VERSION 5.7 ;
  NOWIREEXTENSIONATPIN ON ;
  DIVIDERCHAR "/" ;
  BUSBITCHARS "[]" ;
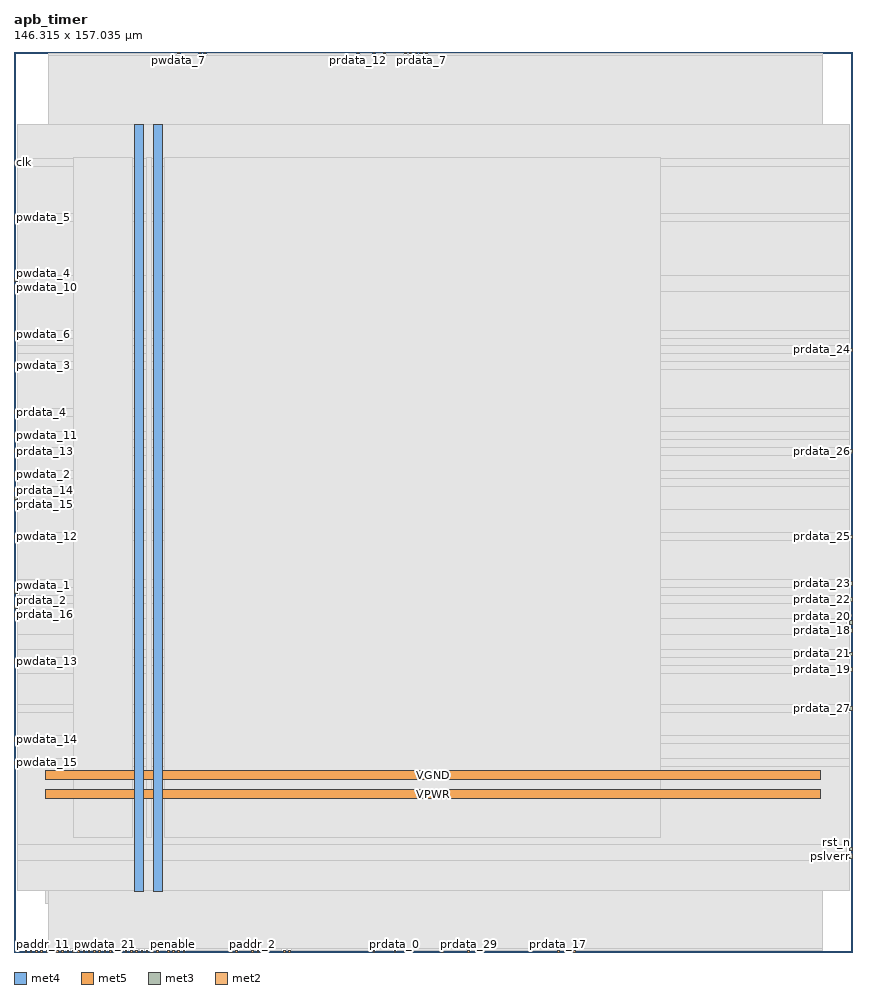
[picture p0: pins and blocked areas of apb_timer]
MACRO apb_timer
  CLASS BLOCK ;
  FOREIGN apb_timer ;
  ORIGIN 0.000 0.000 ;
  SIZE 146.315 BY 157.035 ;
  PIN VGND
    DIRECTION INOUT ;
    USE GROUND ;
    PORT
      LAYER met4 ;
        RECT 24.340 10.640 25.940 144.400 ;
    END
    PORT
      LAYER met5 ;
        RECT 5.520 30.030 140.760 31.630 ;
    END
  END VGND
  PIN VPWR
    DIRECTION INOUT ;
    USE POWER ;
    PORT
      LAYER met4 ;
        RECT 21.040 10.640 22.640 144.400 ;
    END
    PORT
      LAYER met5 ;
        RECT 5.520 26.730 140.760 28.330 ;
    END
  END VPWR
  PIN clk
    DIRECTION INPUT ;
    USE SIGNAL ;
    ANTENNAGATEAREA 1.286700 ;
    ANTENNADIFFAREA 0.434700 ;
    PORT
      LAYER met3 ;
        RECT 0.000 137.400 0.600 138.000 ;
    END
  END clk
  PIN paddr_0
    DIRECTION INPUT ;
    USE SIGNAL ;
    PORT
      LAYER met2 ;
        RECT 1.930 0.000 2.210 0.280 ;
    END
  END paddr_0
  PIN paddr_1
    DIRECTION INPUT ;
    USE SIGNAL ;
    PORT
      LAYER met2 ;
        RECT 2.850 0.000 3.130 0.280 ;
    END
  END paddr_1
  PIN paddr_10
    DIRECTION INPUT ;
    USE SIGNAL ;
    PORT
      LAYER met2 ;
        RECT 3.770 0.000 4.050 0.280 ;
    END
  END paddr_10
  PIN paddr_11
    DIRECTION INPUT ;
    USE SIGNAL ;
    PORT
      LAYER met2 ;
        RECT 4.690 0.000 4.970 0.280 ;
    END
  END paddr_11
  PIN paddr_2
    DIRECTION INPUT ;
    USE SIGNAL ;
    ANTENNAGATEAREA 0.647700 ;
    ANTENNADIFFAREA 0.434700 ;
    PORT
      LAYER met2 ;
        RECT 41.490 0.000 41.770 0.280 ;
    END
  END paddr_2
  PIN paddr_3
    DIRECTION INPUT ;
    USE SIGNAL ;
    ANTENNAGATEAREA 0.647700 ;
    ANTENNADIFFAREA 0.434700 ;
    PORT
      LAYER met2 ;
        RECT 38.730 0.000 39.010 0.280 ;
    END
  END paddr_3
  PIN paddr_4
    DIRECTION INPUT ;
    USE SIGNAL ;
    ANTENNAGATEAREA 0.647700 ;
    ANTENNADIFFAREA 0.434700 ;
    PORT
      LAYER met2 ;
        RECT 37.810 0.000 38.090 0.280 ;
    END
  END paddr_4
  PIN paddr_5
    DIRECTION INPUT ;
    USE SIGNAL ;
    PORT
      LAYER met2 ;
        RECT 5.610 0.000 5.890 0.280 ;
    END
  END paddr_5
  PIN paddr_6
    DIRECTION INPUT ;
    USE SIGNAL ;
    PORT
      LAYER met2 ;
        RECT 6.530 0.000 6.810 0.280 ;
    END
  END paddr_6
  PIN paddr_7
    DIRECTION INPUT ;
    USE SIGNAL ;
    PORT
      LAYER met2 ;
        RECT 7.450 0.000 7.730 0.280 ;
    END
  END paddr_7
  PIN paddr_8
    DIRECTION INPUT ;
    USE SIGNAL ;
    PORT
      LAYER met2 ;
        RECT 8.370 0.000 8.650 0.280 ;
    END
  END paddr_8
  PIN paddr_9
    DIRECTION INPUT ;
    USE SIGNAL ;
    PORT
      LAYER met2 ;
        RECT 9.290 0.000 9.570 0.280 ;
    END
  END paddr_9
  PIN penable
    DIRECTION INPUT ;
    USE SIGNAL ;
    ANTENNAGATEAREA 0.647700 ;
    ANTENNADIFFAREA 0.434700 ;
    PORT
      LAYER met2 ;
        RECT 27.690 0.000 27.970 0.280 ;
    END
  END penable
  PIN prdata_0
    DIRECTION OUTPUT ;
    USE SIGNAL ;
    ANTENNAGATEAREA 0.560700 ;
    ANTENNADIFFAREA 0.863700 ;
    PORT
      LAYER met2 ;
        RECT 66.330 0.000 66.610 0.280 ;
    END
  END prdata_0
  PIN prdata_1
    DIRECTION OUTPUT ;
    USE SIGNAL ;
    ANTENNAGATEAREA 0.560700 ;
    ANTENNADIFFAREA 0.863700 ;
    PORT
      LAYER met2 ;
        RECT 47.010 0.000 47.290 0.280 ;
    END
  END prdata_1
  PIN prdata_10
    DIRECTION OUTPUT ;
    USE SIGNAL ;
    ANTENNAGATEAREA 0.434700 ;
    ANTENNADIFFAREA 1.137600 ;
    PORT
      LAYER met2 ;
        RECT 68.170 156.755 68.450 157.035 ;
    END
  END prdata_10
  PIN prdata_11
    DIRECTION OUTPUT ;
    USE SIGNAL ;
    ANTENNAGATEAREA 0.434700 ;
    ANTENNADIFFAREA 1.137600 ;
    PORT
      LAYER met2 ;
        RECT 69.090 156.755 69.370 157.035 ;
    END
  END prdata_11
  PIN prdata_12
    DIRECTION OUTPUT ;
    USE SIGNAL ;
    ANTENNAGATEAREA 0.434700 ;
    ANTENNADIFFAREA 1.137600 ;
    PORT
      LAYER met2 ;
        RECT 59.890 156.755 60.170 157.035 ;
    END
  END prdata_12
  PIN prdata_13
    DIRECTION OUTPUT ;
    USE SIGNAL ;
    ANTENNAGATEAREA 0.434700 ;
    ANTENNADIFFAREA 1.137600 ;
    PORT
      LAYER met3 ;
        RECT 0.000 87.080 0.600 87.680 ;
    END
  END prdata_13
  PIN prdata_14
    DIRECTION OUTPUT ;
    USE SIGNAL ;
    ANTENNAGATEAREA 0.560700 ;
    ANTENNADIFFAREA 0.863700 ;
    PORT
      LAYER met3 ;
        RECT 0.000 80.280 0.600 80.880 ;
    END
  END prdata_14
  PIN prdata_15
    DIRECTION OUTPUT ;
    USE SIGNAL ;
    ANTENNAGATEAREA 0.434700 ;
    ANTENNADIFFAREA 1.137600 ;
    PORT
      LAYER met3 ;
        RECT 0.000 78.920 0.600 79.520 ;
    END
  END prdata_15
  PIN prdata_16
    DIRECTION OUTPUT ;
    USE SIGNAL ;
    ANTENNAGATEAREA 0.434700 ;
    ANTENNADIFFAREA 1.137600 ;
    PORT
      LAYER met3 ;
        RECT 0.000 58.520 0.600 59.120 ;
    END
  END prdata_16
  PIN prdata_17
    DIRECTION OUTPUT ;
    USE SIGNAL ;
    ANTENNAGATEAREA 0.434700 ;
    ANTENNADIFFAREA 1.137600 ;
    PORT
      LAYER met2 ;
        RECT 94.850 0.000 95.130 0.280 ;
    END
  END prdata_17
  PIN prdata_18
    DIRECTION OUTPUT ;
    USE SIGNAL ;
    ANTENNAGATEAREA 0.434700 ;
    ANTENNADIFFAREA 1.137600 ;
    PORT
      LAYER met3 ;
        RECT 145.715 55.800 146.315 56.400 ;
    END
  END prdata_18
  PIN prdata_19
    DIRECTION OUTPUT ;
    USE SIGNAL ;
    ANTENNAGATEAREA 0.434700 ;
    ANTENNADIFFAREA 1.137600 ;
    PORT
      LAYER met3 ;
        RECT 145.715 49.000 146.315 49.600 ;
    END
  END prdata_19
  PIN prdata_2
    DIRECTION OUTPUT ;
    USE SIGNAL ;
    ANTENNAGATEAREA 0.560700 ;
    ANTENNADIFFAREA 0.863700 ;
    PORT
      LAYER met3 ;
        RECT 0.000 59.880 0.600 60.480 ;
    END
  END prdata_2
  PIN prdata_20
    DIRECTION OUTPUT ;
    USE SIGNAL ;
    ANTENNAGATEAREA 0.434700 ;
    ANTENNADIFFAREA 1.137600 ;
    PORT
      LAYER met3 ;
        RECT 145.715 57.160 146.315 57.760 ;
    END
  END prdata_20
  PIN prdata_21
    DIRECTION OUTPUT ;
    USE SIGNAL ;
    ANTENNAGATEAREA 0.434700 ;
    ANTENNADIFFAREA 1.137600 ;
    PORT
      LAYER met3 ;
        RECT 145.715 51.720 146.315 52.320 ;
    END
  END prdata_21
  PIN prdata_22
    DIRECTION OUTPUT ;
    USE SIGNAL ;
    ANTENNAGATEAREA 0.434700 ;
    ANTENNADIFFAREA 1.137600 ;
    PORT
      LAYER met3 ;
        RECT 145.715 61.240 146.315 61.840 ;
    END
  END prdata_22
  PIN prdata_23
    DIRECTION OUTPUT ;
    USE SIGNAL ;
    ANTENNAGATEAREA 0.434700 ;
    ANTENNADIFFAREA 1.137600 ;
    PORT
      LAYER met3 ;
        RECT 145.715 63.960 146.315 64.560 ;
    END
  END prdata_23
  PIN prdata_24
    DIRECTION OUTPUT ;
    USE SIGNAL ;
    ANTENNAGATEAREA 0.434700 ;
    ANTENNADIFFAREA 1.137600 ;
    PORT
      LAYER met3 ;
        RECT 145.715 104.760 146.315 105.360 ;
    END
  END prdata_24
  PIN prdata_25
    DIRECTION OUTPUT ;
    USE SIGNAL ;
    ANTENNAGATEAREA 0.434700 ;
    ANTENNADIFFAREA 1.137600 ;
    PORT
      LAYER met3 ;
        RECT 145.715 72.120 146.315 72.720 ;
    END
  END prdata_25
  PIN prdata_26
    DIRECTION OUTPUT ;
    USE SIGNAL ;
    ANTENNAGATEAREA 0.434700 ;
    ANTENNADIFFAREA 1.137600 ;
    PORT
      LAYER met3 ;
        RECT 145.715 87.080 146.315 87.680 ;
    END
  END prdata_26
  PIN prdata_27
    DIRECTION OUTPUT ;
    USE SIGNAL ;
    ANTENNAGATEAREA 0.434700 ;
    ANTENNADIFFAREA 1.137600 ;
    PORT
      LAYER met3 ;
        RECT 145.715 42.200 146.315 42.800 ;
    END
  END prdata_27
  PIN prdata_28
    DIRECTION OUTPUT ;
    USE SIGNAL ;
    ANTENNAGATEAREA 0.434700 ;
    ANTENNADIFFAREA 1.137600 ;
    PORT
      LAYER met2 ;
        RECT 97.610 0.000 97.890 0.280 ;
    END
  END prdata_28
  PIN prdata_29
    DIRECTION OUTPUT ;
    USE SIGNAL ;
    ANTENNAGATEAREA 0.434700 ;
    ANTENNADIFFAREA 1.137600 ;
    PORT
      LAYER met2 ;
        RECT 79.210 0.000 79.490 0.280 ;
    END
  END prdata_29
  PIN prdata_3
    DIRECTION OUTPUT ;
    USE SIGNAL ;
    ANTENNAGATEAREA 0.560700 ;
    ANTENNADIFFAREA 0.863700 ;
    PORT
      LAYER met3 ;
        RECT 0.000 77.560 0.600 78.160 ;
    END
  END prdata_3
  PIN prdata_30
    DIRECTION OUTPUT ;
    USE SIGNAL ;
    ANTENNAGATEAREA 0.434700 ;
    ANTENNADIFFAREA 1.137600 ;
    PORT
      LAYER met2 ;
        RECT 74.610 0.000 74.890 0.280 ;
    END
  END prdata_30
  PIN prdata_31
    DIRECTION OUTPUT ;
    USE SIGNAL ;
    ANTENNAGATEAREA 0.560700 ;
    ANTENNADIFFAREA 0.863700 ;
    PORT
      LAYER met2 ;
        RECT 47.930 0.000 48.210 0.280 ;
    END
  END prdata_31
  PIN prdata_4
    DIRECTION OUTPUT ;
    USE SIGNAL ;
    ANTENNAGATEAREA 0.434700 ;
    ANTENNADIFFAREA 1.137600 ;
    PORT
      LAYER met3 ;
        RECT 0.000 93.880 0.600 94.480 ;
    END
  END prdata_4
  PIN prdata_5
    DIRECTION OUTPUT ;
    USE SIGNAL ;
    ANTENNAGATEAREA 0.434700 ;
    ANTENNADIFFAREA 1.137600 ;
    PORT
      LAYER met2 ;
        RECT 64.490 156.755 64.770 157.035 ;
    END
  END prdata_5
  PIN prdata_6
    DIRECTION OUTPUT ;
    USE SIGNAL ;
    ANTENNAGATEAREA 0.434700 ;
    ANTENNADIFFAREA 1.137600 ;
    PORT
      LAYER met2 ;
        RECT 71.850 156.755 72.130 157.035 ;
    END
  END prdata_6
  PIN prdata_7
    DIRECTION OUTPUT ;
    USE SIGNAL ;
    ANTENNAGATEAREA 0.434700 ;
    ANTENNADIFFAREA 1.137600 ;
    PORT
      LAYER met2 ;
        RECT 70.930 156.755 71.210 157.035 ;
    END
  END prdata_7
  PIN prdata_8
    DIRECTION OUTPUT ;
    USE SIGNAL ;
    ANTENNAGATEAREA 0.434700 ;
    ANTENNADIFFAREA 1.137600 ;
    PORT
      LAYER met2 ;
        RECT 70.010 156.755 70.290 157.035 ;
    END
  END prdata_8
  PIN prdata_9
    DIRECTION OUTPUT ;
    USE SIGNAL ;
    ANTENNAGATEAREA 0.434700 ;
    ANTENNADIFFAREA 1.137600 ;
    PORT
      LAYER met2 ;
        RECT 62.650 156.755 62.930 157.035 ;
    END
  END prdata_9
  PIN pready
    DIRECTION OUTPUT ;
    USE SIGNAL ;
    PORT
      LAYER met2 ;
        RECT 10.210 0.000 10.490 0.280 ;
    END
  END pready
  PIN psel
    DIRECTION INPUT ;
    USE SIGNAL ;
    ANTENNAGATEAREA 0.647700 ;
    ANTENNADIFFAREA 0.434700 ;
    PORT
      LAYER met2 ;
        RECT 28.610 0.000 28.890 0.280 ;
    END
  END psel
  PIN pslverr
    DIRECTION OUTPUT ;
    USE SIGNAL ;
    ANTENNAGATEAREA 0.434700 ;
    ANTENNADIFFAREA 0.775300 ;
    PORT
      LAYER met3 ;
        RECT 145.715 16.360 146.315 16.960 ;
    END
  END pslverr
  PIN pwdata_0
    DIRECTION INPUT ;
    USE SIGNAL ;
    ANTENNAGATEAREA 0.647700 ;
    ANTENNADIFFAREA 0.434700 ;
    PORT
      LAYER met2 ;
        RECT 29.530 0.000 29.810 0.280 ;
    END
  END pwdata_0
  PIN pwdata_1
    DIRECTION INPUT ;
    USE SIGNAL ;
    ANTENNAGATEAREA 0.647700 ;
    ANTENNADIFFAREA 0.434700 ;
    PORT
      LAYER met3 ;
        RECT 0.000 62.600 0.600 63.200 ;
    END
  END pwdata_1
  PIN pwdata_10
    DIRECTION INPUT ;
    USE SIGNAL ;
    ANTENNAGATEAREA 0.647700 ;
    ANTENNADIFFAREA 0.434700 ;
    PORT
      LAYER met3 ;
        RECT 0.000 115.640 0.600 116.240 ;
    END
  END pwdata_10
  PIN pwdata_11
    DIRECTION INPUT ;
    USE SIGNAL ;
    ANTENNAGATEAREA 0.647700 ;
    ANTENNADIFFAREA 0.434700 ;
    PORT
      LAYER met3 ;
        RECT 0.000 89.800 0.600 90.400 ;
    END
  END pwdata_11
  PIN pwdata_12
    DIRECTION INPUT ;
    USE SIGNAL ;
    ANTENNAGATEAREA 0.647700 ;
    ANTENNADIFFAREA 0.434700 ;
    PORT
      LAYER met3 ;
        RECT 0.000 72.120 0.600 72.720 ;
    END
  END pwdata_12
  PIN pwdata_13
    DIRECTION INPUT ;
    USE SIGNAL ;
    ANTENNAGATEAREA 0.647700 ;
    ANTENNADIFFAREA 0.434700 ;
    PORT
      LAYER met3 ;
        RECT 0.000 50.360 0.600 50.960 ;
    END
  END pwdata_13
  PIN pwdata_14
    DIRECTION INPUT ;
    USE SIGNAL ;
    ANTENNAGATEAREA 0.647700 ;
    ANTENNADIFFAREA 0.434700 ;
    PORT
      LAYER met3 ;
        RECT 0.000 36.760 0.600 37.360 ;
    END
  END pwdata_14
  PIN pwdata_15
    DIRECTION INPUT ;
    USE SIGNAL ;
    ANTENNAGATEAREA 0.647700 ;
    ANTENNADIFFAREA 0.434700 ;
    PORT
      LAYER met3 ;
        RECT 0.000 32.680 0.600 33.280 ;
    END
  END pwdata_15
  PIN pwdata_16
    DIRECTION INPUT ;
    USE SIGNAL ;
    PORT
      LAYER met2 ;
        RECT 11.130 0.000 11.410 0.280 ;
    END
  END pwdata_16
  PIN pwdata_17
    DIRECTION INPUT ;
    USE SIGNAL ;
    PORT
      LAYER met2 ;
        RECT 12.050 0.000 12.330 0.280 ;
    END
  END pwdata_17
  PIN pwdata_18
    DIRECTION INPUT ;
    USE SIGNAL ;
    PORT
      LAYER met2 ;
        RECT 12.970 0.000 13.250 0.280 ;
    END
  END pwdata_18
  PIN pwdata_19
    DIRECTION INPUT ;
    USE SIGNAL ;
    PORT
      LAYER met2 ;
        RECT 13.890 0.000 14.170 0.280 ;
    END
  END pwdata_19
  PIN pwdata_2
    DIRECTION INPUT ;
    USE SIGNAL ;
    ANTENNAGATEAREA 0.647700 ;
    ANTENNADIFFAREA 0.434700 ;
    PORT
      LAYER met3 ;
        RECT 0.000 83.000 0.600 83.600 ;
    END
  END pwdata_2
  PIN pwdata_20
    DIRECTION INPUT ;
    USE SIGNAL ;
    PORT
      LAYER met2 ;
        RECT 14.810 0.000 15.090 0.280 ;
    END
  END pwdata_20
  PIN pwdata_21
    DIRECTION INPUT ;
    USE SIGNAL ;
    PORT
      LAYER met2 ;
        RECT 15.730 0.000 16.010 0.280 ;
    END
  END pwdata_21
  PIN pwdata_22
    DIRECTION INPUT ;
    USE SIGNAL ;
    PORT
      LAYER met2 ;
        RECT 16.650 0.000 16.930 0.280 ;
    END
  END pwdata_22
  PIN pwdata_23
    DIRECTION INPUT ;
    USE SIGNAL ;
    PORT
      LAYER met2 ;
        RECT 17.570 0.000 17.850 0.280 ;
    END
  END pwdata_23
  PIN pwdata_24
    DIRECTION INPUT ;
    USE SIGNAL ;
    PORT
      LAYER met2 ;
        RECT 18.490 0.000 18.770 0.280 ;
    END
  END pwdata_24
  PIN pwdata_25
    DIRECTION INPUT ;
    USE SIGNAL ;
    PORT
      LAYER met2 ;
        RECT 19.410 0.000 19.690 0.280 ;
    END
  END pwdata_25
  PIN pwdata_26
    DIRECTION INPUT ;
    USE SIGNAL ;
    PORT
      LAYER met2 ;
        RECT 20.330 0.000 20.610 0.280 ;
    END
  END pwdata_26
  PIN pwdata_27
    DIRECTION INPUT ;
    USE SIGNAL ;
    PORT
      LAYER met2 ;
        RECT 21.250 0.000 21.530 0.280 ;
    END
  END pwdata_27
  PIN pwdata_28
    DIRECTION INPUT ;
    USE SIGNAL ;
    PORT
      LAYER met2 ;
        RECT 22.170 0.000 22.450 0.280 ;
    END
  END pwdata_28
  PIN pwdata_29
    DIRECTION INPUT ;
    USE SIGNAL ;
    PORT
      LAYER met2 ;
        RECT 23.090 0.000 23.370 0.280 ;
    END
  END pwdata_29
  PIN pwdata_3
    DIRECTION INPUT ;
    USE SIGNAL ;
    ANTENNAGATEAREA 0.647700 ;
    ANTENNADIFFAREA 0.434700 ;
    PORT
      LAYER met3 ;
        RECT 0.000 102.040 0.600 102.640 ;
    END
  END pwdata_3
  PIN pwdata_30
    DIRECTION INPUT ;
    USE SIGNAL ;
    PORT
      LAYER met2 ;
        RECT 24.010 0.000 24.290 0.280 ;
    END
  END pwdata_30
  PIN pwdata_31
    DIRECTION INPUT ;
    USE SIGNAL ;
    PORT
      LAYER met2 ;
        RECT 24.930 0.000 25.210 0.280 ;
    END
  END pwdata_31
  PIN pwdata_4
    DIRECTION INPUT ;
    USE SIGNAL ;
    ANTENNAGATEAREA 0.647700 ;
    ANTENNADIFFAREA 0.434700 ;
    PORT
      LAYER met3 ;
        RECT 0.000 117.000 0.600 117.600 ;
    END
  END pwdata_4
  PIN pwdata_5
    DIRECTION INPUT ;
    USE SIGNAL ;
    ANTENNAGATEAREA 0.647700 ;
    ANTENNADIFFAREA 0.434700 ;
    PORT
      LAYER met3 ;
        RECT 0.000 127.880 0.600 128.480 ;
    END
  END pwdata_5
  PIN pwdata_6
    DIRECTION INPUT ;
    USE SIGNAL ;
    ANTENNAGATEAREA 0.647700 ;
    ANTENNADIFFAREA 0.434700 ;
    PORT
      LAYER met3 ;
        RECT 0.000 107.480 0.600 108.080 ;
    END
  END pwdata_6
  PIN pwdata_7
    DIRECTION INPUT ;
    USE SIGNAL ;
    ANTENNAGATEAREA 0.647700 ;
    ANTENNADIFFAREA 0.434700 ;
    PORT
      LAYER met2 ;
        RECT 28.610 156.755 28.890 157.035 ;
    END
  END pwdata_7
  PIN pwdata_8
    DIRECTION INPUT ;
    USE SIGNAL ;
    ANTENNAGATEAREA 0.647700 ;
    ANTENNADIFFAREA 0.434700 ;
    PORT
      LAYER met2 ;
        RECT 33.210 156.755 33.490 157.035 ;
    END
  END pwdata_8
  PIN pwdata_9
    DIRECTION INPUT ;
    USE SIGNAL ;
    ANTENNAGATEAREA 0.647700 ;
    ANTENNADIFFAREA 0.434700 ;
    PORT
      LAYER met2 ;
        RECT 32.290 156.755 32.570 157.035 ;
    END
  END pwdata_9
  PIN pwrite
    DIRECTION INPUT ;
    USE SIGNAL ;
    ANTENNAGATEAREA 0.647700 ;
    ANTENNADIFFAREA 0.434700 ;
    PORT
      LAYER met2 ;
        RECT 26.770 0.000 27.050 0.280 ;
    END
  END pwrite
  PIN rst_n
    DIRECTION INPUT ;
    USE SIGNAL ;
    ANTENNAGATEAREA 0.647700 ;
    ANTENNADIFFAREA 0.434700 ;
    PORT
      LAYER met3 ;
        RECT 145.715 17.720 146.315 18.320 ;
    END
  END rst_n
  PIN sw_irq
    DIRECTION OUTPUT ;
    USE SIGNAL ;
    ANTENNAGATEAREA 0.434700 ;
    ANTENNADIFFAREA 1.137600 ;
    PORT
      LAYER met2 ;
        RECT 42.410 0.000 42.690 0.280 ;
    END
  END sw_irq
  PIN timer_irq
    DIRECTION OUTPUT ;
    USE SIGNAL ;
    ANTENNAGATEAREA 0.434700 ;
    ANTENNADIFFAREA 1.137600 ;
    PORT
      LAYER met2 ;
        RECT 62.650 0.000 62.930 0.280 ;
    END
  END timer_irq
  OBS
      LAYER nwell ;
        RECT 5.330 10.795 140.950 144.350 ;
      LAYER li1 ;
        RECT 5.520 10.795 140.760 144.245 ;
      LAYER met1 ;
        RECT 5.520 8.540 141.150 144.400 ;
      LAYER met2 ;
        RECT 6.070 156.475 28.330 156.755 ;
        RECT 29.170 156.475 32.010 156.755 ;
        RECT 32.850 156.475 32.930 156.755 ;
        RECT 33.770 156.475 59.610 156.755 ;
        RECT 60.450 156.475 62.370 156.755 ;
        RECT 63.210 156.475 64.210 156.755 ;
        RECT 65.050 156.475 67.890 156.755 ;
        RECT 68.730 156.475 68.810 156.755 ;
        RECT 69.650 156.475 69.730 156.755 ;
        RECT 70.570 156.475 70.650 156.755 ;
        RECT 71.490 156.475 71.570 156.755 ;
        RECT 72.410 156.475 141.120 156.755 ;
        RECT 6.070 0.560 141.120 156.475 ;
        RECT 6.170 0.280 6.250 0.560 ;
        RECT 7.090 0.280 7.170 0.560 ;
        RECT 8.010 0.280 8.090 0.560 ;
        RECT 8.930 0.280 9.010 0.560 ;
        RECT 9.850 0.280 9.930 0.560 ;
        RECT 10.770 0.280 10.850 0.560 ;
        RECT 11.690 0.280 11.770 0.560 ;
        RECT 12.610 0.280 12.690 0.560 ;
        RECT 13.530 0.280 13.610 0.560 ;
        RECT 14.450 0.280 14.530 0.560 ;
        RECT 15.370 0.280 15.450 0.560 ;
        RECT 16.290 0.280 16.370 0.560 ;
        RECT 17.210 0.280 17.290 0.560 ;
        RECT 18.130 0.280 18.210 0.560 ;
        RECT 19.050 0.280 19.130 0.560 ;
        RECT 19.970 0.280 20.050 0.560 ;
        RECT 20.890 0.280 20.970 0.560 ;
        RECT 21.810 0.280 21.890 0.560 ;
        RECT 22.730 0.280 22.810 0.560 ;
        RECT 23.650 0.280 23.730 0.560 ;
        RECT 24.570 0.280 24.650 0.560 ;
        RECT 25.490 0.280 26.490 0.560 ;
        RECT 27.330 0.280 27.410 0.560 ;
        RECT 28.250 0.280 28.330 0.560 ;
        RECT 29.170 0.280 29.250 0.560 ;
        RECT 30.090 0.280 37.530 0.560 ;
        RECT 38.370 0.280 38.450 0.560 ;
        RECT 39.290 0.280 41.210 0.560 ;
        RECT 42.050 0.280 42.130 0.560 ;
        RECT 42.970 0.280 46.730 0.560 ;
        RECT 47.570 0.280 47.650 0.560 ;
        RECT 48.490 0.280 62.370 0.560 ;
        RECT 63.210 0.280 66.050 0.560 ;
        RECT 66.890 0.280 74.330 0.560 ;
        RECT 75.170 0.280 78.930 0.560 ;
        RECT 79.770 0.280 94.570 0.560 ;
        RECT 95.410 0.280 97.330 0.560 ;
        RECT 98.170 0.280 141.120 0.560 ;
      LAYER met3 ;
        RECT 0.600 138.400 145.715 144.325 ;
        RECT 1.000 137.000 145.715 138.400 ;
        RECT 0.600 128.880 145.715 137.000 ;
        RECT 1.000 127.480 145.715 128.880 ;
        RECT 0.600 118.000 145.715 127.480 ;
        RECT 1.000 115.240 145.715 118.000 ;
        RECT 0.600 108.480 145.715 115.240 ;
        RECT 1.000 107.080 145.715 108.480 ;
        RECT 0.600 105.760 145.715 107.080 ;
        RECT 0.600 104.360 145.315 105.760 ;
        RECT 0.600 103.040 145.715 104.360 ;
        RECT 1.000 101.640 145.715 103.040 ;
        RECT 0.600 94.880 145.715 101.640 ;
        RECT 1.000 93.480 145.715 94.880 ;
        RECT 0.600 90.800 145.715 93.480 ;
        RECT 1.000 89.400 145.715 90.800 ;
        RECT 0.600 88.080 145.715 89.400 ;
        RECT 1.000 86.680 145.315 88.080 ;
        RECT 0.600 84.000 145.715 86.680 ;
        RECT 1.000 82.600 145.715 84.000 ;
        RECT 0.600 81.280 145.715 82.600 ;
        RECT 1.000 77.160 145.715 81.280 ;
        RECT 0.600 73.120 145.715 77.160 ;
        RECT 1.000 71.720 145.315 73.120 ;
        RECT 0.600 64.960 145.715 71.720 ;
        RECT 0.600 63.600 145.315 64.960 ;
        RECT 1.000 63.560 145.315 63.600 ;
        RECT 1.000 62.240 145.715 63.560 ;
        RECT 1.000 62.200 145.315 62.240 ;
        RECT 0.600 60.880 145.315 62.200 ;
        RECT 1.000 60.840 145.315 60.880 ;
        RECT 1.000 58.160 145.715 60.840 ;
        RECT 1.000 58.120 145.315 58.160 ;
        RECT 0.600 55.400 145.315 58.120 ;
        RECT 0.600 52.720 145.715 55.400 ;
        RECT 0.600 51.360 145.315 52.720 ;
        RECT 1.000 51.320 145.315 51.360 ;
        RECT 1.000 50.000 145.715 51.320 ;
        RECT 1.000 49.960 145.315 50.000 ;
        RECT 0.600 48.600 145.315 49.960 ;
        RECT 0.600 43.200 145.715 48.600 ;
        RECT 0.600 41.800 145.315 43.200 ;
        RECT 0.600 37.760 145.715 41.800 ;
        RECT 1.000 36.360 145.715 37.760 ;
        RECT 0.600 33.680 145.715 36.360 ;
        RECT 1.000 32.280 145.715 33.680 ;
        RECT 0.600 18.720 145.715 32.280 ;
        RECT 0.600 15.960 145.315 18.720 ;
        RECT 0.600 10.715 145.715 15.960 ;
      LAYER met4 ;
        RECT 10.415 19.895 20.640 138.545 ;
        RECT 23.040 19.895 23.940 138.545 ;
        RECT 26.340 19.895 112.865 138.545 ;
  END
END apb_timer
END LIBRARY

